VERSION 5.8 ;
BUSBITCHARS "[]" ;
DIVIDERCHAR "/" ;
UNITS
    DATABASE MICRONS 1000 ;
END UNITS

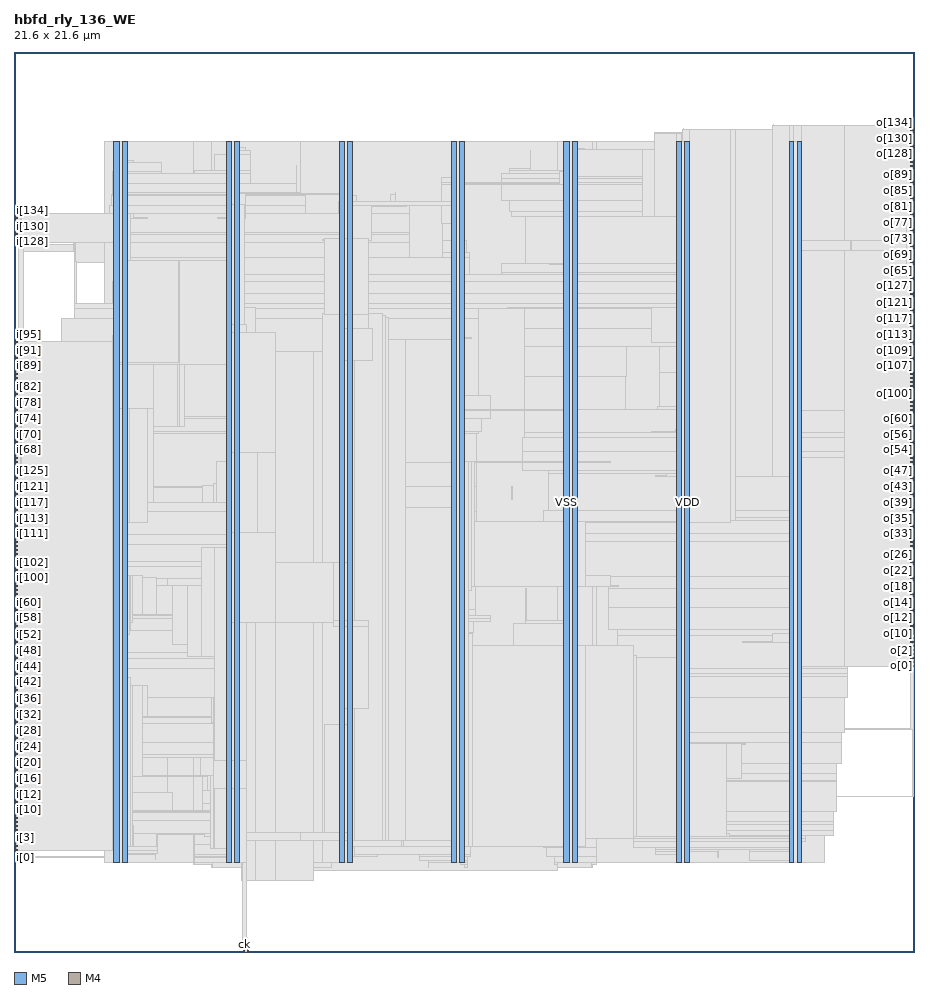
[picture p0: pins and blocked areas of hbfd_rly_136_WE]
MACRO hbfd_rly_136_WE
  FOREIGN hbfd_rly_136_WE 0 0 ;
  CLASS BLOCK ;
  SIZE 21.6 BY 21.6 ;
  PIN ck
    DIRECTION INPUT ;
    USE SIGNAL ;
    PORT
      LAYER M5 ;
        RECT  5.52 0 5.544 0.084 ;
    END
  END ck
  PIN i[0]
    DIRECTION INPUT ;
    USE SIGNAL ;
    PORT
      LAYER M4 ;
        RECT  0 2.448 0.084 2.472 ;
    END
  END i[0]
  PIN i[100]
    DIRECTION INPUT ;
    USE SIGNAL ;
    PORT
      LAYER M4 ;
        RECT  0 8.976 0.084 9 ;
    END
  END i[100]
  PIN i[101]
    DIRECTION INPUT ;
    USE SIGNAL ;
    PORT
      LAYER M4 ;
        RECT  0 9.072 0.084 9.096 ;
    END
  END i[101]
  PIN i[102]
    DIRECTION INPUT ;
    USE SIGNAL ;
    PORT
      LAYER M4 ;
        RECT  0 9.168 0.084 9.192 ;
    END
  END i[102]
  PIN i[103]
    DIRECTION INPUT ;
    USE SIGNAL ;
    PORT
      LAYER M4 ;
        RECT  0 9.264 0.084 9.288 ;
    END
  END i[103]
  PIN i[104]
    DIRECTION INPUT ;
    USE SIGNAL ;
    PORT
      LAYER M4 ;
        RECT  0 9.36 0.084 9.384 ;
    END
  END i[104]
  PIN i[105]
    DIRECTION INPUT ;
    USE SIGNAL ;
    PORT
      LAYER M4 ;
        RECT  0 9.456 0.084 9.48 ;
    END
  END i[105]
  PIN i[106]
    DIRECTION INPUT ;
    USE SIGNAL ;
    PORT
      LAYER M4 ;
        RECT  0 9.552 0.084 9.576 ;
    END
  END i[106]
  PIN i[107]
    DIRECTION INPUT ;
    USE SIGNAL ;
    PORT
      LAYER M4 ;
        RECT  0 9.648 0.084 9.672 ;
    END
  END i[107]
  PIN i[108]
    DIRECTION INPUT ;
    USE SIGNAL ;
    PORT
      LAYER M4 ;
        RECT  0 9.744 0.084 9.768 ;
    END
  END i[108]
  PIN i[109]
    DIRECTION INPUT ;
    USE SIGNAL ;
    PORT
      LAYER M4 ;
        RECT  0 9.84 0.084 9.864 ;
    END
  END i[109]
  PIN i[10]
    DIRECTION INPUT ;
    USE SIGNAL ;
    PORT
      LAYER M4 ;
        RECT  0 3.408 0.084 3.432 ;
    END
  END i[10]
  PIN i[110]
    DIRECTION INPUT ;
    USE SIGNAL ;
    PORT
      LAYER M4 ;
        RECT  0 9.936 0.084 9.96 ;
    END
  END i[110]
  PIN i[111]
    DIRECTION INPUT ;
    USE SIGNAL ;
    PORT
      LAYER M4 ;
        RECT  0 10.032 0.084 10.056 ;
    END
  END i[111]
  PIN i[112]
    DIRECTION INPUT ;
    USE SIGNAL ;
    PORT
      LAYER M4 ;
        RECT  0 10.128 0.084 10.152 ;
    END
  END i[112]
  PIN i[113]
    DIRECTION INPUT ;
    USE SIGNAL ;
    PORT
      LAYER M4 ;
        RECT  0 10.224 0.084 10.248 ;
    END
  END i[113]
  PIN i[114]
    DIRECTION INPUT ;
    USE SIGNAL ;
    PORT
      LAYER M4 ;
        RECT  0 10.32 0.084 10.344 ;
    END
  END i[114]
  PIN i[115]
    DIRECTION INPUT ;
    USE SIGNAL ;
    PORT
      LAYER M4 ;
        RECT  0 10.416 0.084 10.44 ;
    END
  END i[115]
  PIN i[116]
    DIRECTION INPUT ;
    USE SIGNAL ;
    PORT
      LAYER M4 ;
        RECT  0 10.512 0.084 10.536 ;
    END
  END i[116]
  PIN i[117]
    DIRECTION INPUT ;
    USE SIGNAL ;
    PORT
      LAYER M4 ;
        RECT  0 10.608 0.084 10.632 ;
    END
  END i[117]
  PIN i[118]
    DIRECTION INPUT ;
    USE SIGNAL ;
    PORT
      LAYER M4 ;
        RECT  0 10.704 0.084 10.728 ;
    END
  END i[118]
  PIN i[119]
    DIRECTION INPUT ;
    USE SIGNAL ;
    PORT
      LAYER M4 ;
        RECT  0 10.8 0.084 10.824 ;
    END
  END i[119]
  PIN i[11]
    DIRECTION INPUT ;
    USE SIGNAL ;
    PORT
      LAYER M4 ;
        RECT  0 3.504 0.084 3.528 ;
    END
  END i[11]
  PIN i[120]
    DIRECTION INPUT ;
    USE SIGNAL ;
    PORT
      LAYER M4 ;
        RECT  0 10.896 0.084 10.92 ;
    END
  END i[120]
  PIN i[121]
    DIRECTION INPUT ;
    USE SIGNAL ;
    PORT
      LAYER M4 ;
        RECT  0 10.992 0.084 11.016 ;
    END
  END i[121]
  PIN i[122]
    DIRECTION INPUT ;
    USE SIGNAL ;
    PORT
      LAYER M4 ;
        RECT  0 11.088 0.084 11.112 ;
    END
  END i[122]
  PIN i[123]
    DIRECTION INPUT ;
    USE SIGNAL ;
    PORT
      LAYER M4 ;
        RECT  0 11.184 0.084 11.208 ;
    END
  END i[123]
  PIN i[124]
    DIRECTION INPUT ;
    USE SIGNAL ;
    PORT
      LAYER M4 ;
        RECT  0 11.28 0.084 11.304 ;
    END
  END i[124]
  PIN i[125]
    DIRECTION INPUT ;
    USE SIGNAL ;
    PORT
      LAYER M4 ;
        RECT  0 11.376 0.084 11.4 ;
    END
  END i[125]
  PIN i[126]
    DIRECTION INPUT ;
    USE SIGNAL ;
    PORT
      LAYER M4 ;
        RECT  0 11.472 0.084 11.496 ;
    END
  END i[126]
  PIN i[127]
    DIRECTION INPUT ;
    USE SIGNAL ;
    PORT
      LAYER M4 ;
        RECT  0 11.568 0.084 11.592 ;
    END
  END i[127]
  PIN i[128]
    DIRECTION INPUT ;
    USE SIGNAL ;
    PORT
      LAYER M4 ;
        RECT  0 17.04 0.084 17.064 ;
    END
  END i[128]
  PIN i[129]
    DIRECTION INPUT ;
    USE SIGNAL ;
    PORT
      LAYER M4 ;
        RECT  0 17.136 0.084 17.16 ;
    END
  END i[129]
  PIN i[12]
    DIRECTION INPUT ;
    USE SIGNAL ;
    PORT
      LAYER M4 ;
        RECT  0 3.6 0.084 3.624 ;
    END
  END i[12]
  PIN i[130]
    DIRECTION INPUT ;
    USE SIGNAL ;
    PORT
      LAYER M4 ;
        RECT  0 17.232 0.084 17.256 ;
    END
  END i[130]
  PIN i[131]
    DIRECTION INPUT ;
    USE SIGNAL ;
    PORT
      LAYER M4 ;
        RECT  0 17.328 0.084 17.352 ;
    END
  END i[131]
  PIN i[132]
    DIRECTION INPUT ;
    USE SIGNAL ;
    PORT
      LAYER M4 ;
        RECT  0 17.424 0.084 17.448 ;
    END
  END i[132]
  PIN i[133]
    DIRECTION INPUT ;
    USE SIGNAL ;
    PORT
      LAYER M4 ;
        RECT  0 17.52 0.084 17.544 ;
    END
  END i[133]
  PIN i[134]
    DIRECTION INPUT ;
    USE SIGNAL ;
    PORT
      LAYER M4 ;
        RECT  0 17.616 0.084 17.64 ;
    END
  END i[134]
  PIN i[135]
    DIRECTION INPUT ;
    USE SIGNAL ;
    PORT
      LAYER M4 ;
        RECT  0 17.712 0.084 17.736 ;
    END
  END i[135]
  PIN i[13]
    DIRECTION INPUT ;
    USE SIGNAL ;
    PORT
      LAYER M4 ;
        RECT  0 3.696 0.084 3.72 ;
    END
  END i[13]
  PIN i[14]
    DIRECTION INPUT ;
    USE SIGNAL ;
    PORT
      LAYER M4 ;
        RECT  0 3.792 0.084 3.816 ;
    END
  END i[14]
  PIN i[15]
    DIRECTION INPUT ;
    USE SIGNAL ;
    PORT
      LAYER M4 ;
        RECT  0 3.888 0.084 3.912 ;
    END
  END i[15]
  PIN i[16]
    DIRECTION INPUT ;
    USE SIGNAL ;
    PORT
      LAYER M4 ;
        RECT  0 3.984 0.084 4.008 ;
    END
  END i[16]
  PIN i[17]
    DIRECTION INPUT ;
    USE SIGNAL ;
    PORT
      LAYER M4 ;
        RECT  0 4.08 0.084 4.104 ;
    END
  END i[17]
  PIN i[18]
    DIRECTION INPUT ;
    USE SIGNAL ;
    PORT
      LAYER M4 ;
        RECT  0 4.176 0.084 4.2 ;
    END
  END i[18]
  PIN i[19]
    DIRECTION INPUT ;
    USE SIGNAL ;
    PORT
      LAYER M4 ;
        RECT  0 4.272 0.084 4.296 ;
    END
  END i[19]
  PIN i[1]
    DIRECTION INPUT ;
    USE SIGNAL ;
    PORT
      LAYER M4 ;
        RECT  0 2.544 0.084 2.568 ;
    END
  END i[1]
  PIN i[20]
    DIRECTION INPUT ;
    USE SIGNAL ;
    PORT
      LAYER M4 ;
        RECT  0 4.368 0.084 4.392 ;
    END
  END i[20]
  PIN i[21]
    DIRECTION INPUT ;
    USE SIGNAL ;
    PORT
      LAYER M4 ;
        RECT  0 4.464 0.084 4.488 ;
    END
  END i[21]
  PIN i[22]
    DIRECTION INPUT ;
    USE SIGNAL ;
    PORT
      LAYER M4 ;
        RECT  0 4.56 0.084 4.584 ;
    END
  END i[22]
  PIN i[23]
    DIRECTION INPUT ;
    USE SIGNAL ;
    PORT
      LAYER M4 ;
        RECT  0 4.656 0.084 4.68 ;
    END
  END i[23]
  PIN i[24]
    DIRECTION INPUT ;
    USE SIGNAL ;
    PORT
      LAYER M4 ;
        RECT  0 4.752 0.084 4.776 ;
    END
  END i[24]
  PIN i[25]
    DIRECTION INPUT ;
    USE SIGNAL ;
    PORT
      LAYER M4 ;
        RECT  0 4.848 0.084 4.872 ;
    END
  END i[25]
  PIN i[26]
    DIRECTION INPUT ;
    USE SIGNAL ;
    PORT
      LAYER M4 ;
        RECT  0 4.944 0.084 4.968 ;
    END
  END i[26]
  PIN i[27]
    DIRECTION INPUT ;
    USE SIGNAL ;
    PORT
      LAYER M4 ;
        RECT  0 5.04 0.084 5.064 ;
    END
  END i[27]
  PIN i[28]
    DIRECTION INPUT ;
    USE SIGNAL ;
    PORT
      LAYER M4 ;
        RECT  0 5.136 0.084 5.16 ;
    END
  END i[28]
  PIN i[29]
    DIRECTION INPUT ;
    USE SIGNAL ;
    PORT
      LAYER M4 ;
        RECT  0 5.232 0.084 5.256 ;
    END
  END i[29]
  PIN i[2]
    DIRECTION INPUT ;
    USE SIGNAL ;
    PORT
      LAYER M4 ;
        RECT  0 2.64 0.084 2.664 ;
    END
  END i[2]
  PIN i[30]
    DIRECTION INPUT ;
    USE SIGNAL ;
    PORT
      LAYER M4 ;
        RECT  0 5.328 0.084 5.352 ;
    END
  END i[30]
  PIN i[31]
    DIRECTION INPUT ;
    USE SIGNAL ;
    PORT
      LAYER M4 ;
        RECT  0 5.424 0.084 5.448 ;
    END
  END i[31]
  PIN i[32]
    DIRECTION INPUT ;
    USE SIGNAL ;
    PORT
      LAYER M4 ;
        RECT  0 5.52 0.084 5.544 ;
    END
  END i[32]
  PIN i[33]
    DIRECTION INPUT ;
    USE SIGNAL ;
    PORT
      LAYER M4 ;
        RECT  0 5.616 0.084 5.64 ;
    END
  END i[33]
  PIN i[34]
    DIRECTION INPUT ;
    USE SIGNAL ;
    PORT
      LAYER M4 ;
        RECT  0 5.712 0.084 5.736 ;
    END
  END i[34]
  PIN i[35]
    DIRECTION INPUT ;
    USE SIGNAL ;
    PORT
      LAYER M4 ;
        RECT  0 5.808 0.084 5.832 ;
    END
  END i[35]
  PIN i[36]
    DIRECTION INPUT ;
    USE SIGNAL ;
    PORT
      LAYER M4 ;
        RECT  0 5.904 0.084 5.928 ;
    END
  END i[36]
  PIN i[37]
    DIRECTION INPUT ;
    USE SIGNAL ;
    PORT
      LAYER M4 ;
        RECT  0 6 0.084 6.024 ;
    END
  END i[37]
  PIN i[38]
    DIRECTION INPUT ;
    USE SIGNAL ;
    PORT
      LAYER M4 ;
        RECT  0 6.096 0.084 6.12 ;
    END
  END i[38]
  PIN i[39]
    DIRECTION INPUT ;
    USE SIGNAL ;
    PORT
      LAYER M4 ;
        RECT  0 6.192 0.084 6.216 ;
    END
  END i[39]
  PIN i[3]
    DIRECTION INPUT ;
    USE SIGNAL ;
    PORT
      LAYER M4 ;
        RECT  0 2.736 0.084 2.76 ;
    END
  END i[3]
  PIN i[40]
    DIRECTION INPUT ;
    USE SIGNAL ;
    PORT
      LAYER M4 ;
        RECT  0 6.288 0.084 6.312 ;
    END
  END i[40]
  PIN i[41]
    DIRECTION INPUT ;
    USE SIGNAL ;
    PORT
      LAYER M4 ;
        RECT  0 6.384 0.084 6.408 ;
    END
  END i[41]
  PIN i[42]
    DIRECTION INPUT ;
    USE SIGNAL ;
    PORT
      LAYER M4 ;
        RECT  0 6.48 0.084 6.504 ;
    END
  END i[42]
  PIN i[43]
    DIRECTION INPUT ;
    USE SIGNAL ;
    PORT
      LAYER M4 ;
        RECT  0 6.576 0.084 6.6 ;
    END
  END i[43]
  PIN i[44]
    DIRECTION INPUT ;
    USE SIGNAL ;
    PORT
      LAYER M4 ;
        RECT  0 6.672 0.084 6.696 ;
    END
  END i[44]
  PIN i[45]
    DIRECTION INPUT ;
    USE SIGNAL ;
    PORT
      LAYER M4 ;
        RECT  0 6.768 0.084 6.792 ;
    END
  END i[45]
  PIN i[46]
    DIRECTION INPUT ;
    USE SIGNAL ;
    PORT
      LAYER M4 ;
        RECT  0 6.864 0.084 6.888 ;
    END
  END i[46]
  PIN i[47]
    DIRECTION INPUT ;
    USE SIGNAL ;
    PORT
      LAYER M4 ;
        RECT  0 6.96 0.084 6.984 ;
    END
  END i[47]
  PIN i[48]
    DIRECTION INPUT ;
    USE SIGNAL ;
    PORT
      LAYER M4 ;
        RECT  0 7.056 0.084 7.08 ;
    END
  END i[48]
  PIN i[49]
    DIRECTION INPUT ;
    USE SIGNAL ;
    PORT
      LAYER M4 ;
        RECT  0 7.152 0.084 7.176 ;
    END
  END i[49]
  PIN i[4]
    DIRECTION INPUT ;
    USE SIGNAL ;
    PORT
      LAYER M4 ;
        RECT  0 2.832 0.084 2.856 ;
    END
  END i[4]
  PIN i[50]
    DIRECTION INPUT ;
    USE SIGNAL ;
    PORT
      LAYER M4 ;
        RECT  0 7.248 0.084 7.272 ;
    END
  END i[50]
  PIN i[51]
    DIRECTION INPUT ;
    USE SIGNAL ;
    PORT
      LAYER M4 ;
        RECT  0 7.344 0.084 7.368 ;
    END
  END i[51]
  PIN i[52]
    DIRECTION INPUT ;
    USE SIGNAL ;
    PORT
      LAYER M4 ;
        RECT  0 7.44 0.084 7.464 ;
    END
  END i[52]
  PIN i[53]
    DIRECTION INPUT ;
    USE SIGNAL ;
    PORT
      LAYER M4 ;
        RECT  0 7.536 0.084 7.56 ;
    END
  END i[53]
  PIN i[54]
    DIRECTION INPUT ;
    USE SIGNAL ;
    PORT
      LAYER M4 ;
        RECT  0 7.632 0.084 7.656 ;
    END
  END i[54]
  PIN i[55]
    DIRECTION INPUT ;
    USE SIGNAL ;
    PORT
      LAYER M4 ;
        RECT  0 7.728 0.084 7.752 ;
    END
  END i[55]
  PIN i[56]
    DIRECTION INPUT ;
    USE SIGNAL ;
    PORT
      LAYER M4 ;
        RECT  0 7.824 0.084 7.848 ;
    END
  END i[56]
  PIN i[57]
    DIRECTION INPUT ;
    USE SIGNAL ;
    PORT
      LAYER M4 ;
        RECT  0 7.92 0.084 7.944 ;
    END
  END i[57]
  PIN i[58]
    DIRECTION INPUT ;
    USE SIGNAL ;
    PORT
      LAYER M4 ;
        RECT  0 8.016 0.084 8.04 ;
    END
  END i[58]
  PIN i[59]
    DIRECTION INPUT ;
    USE SIGNAL ;
    PORT
      LAYER M4 ;
        RECT  0 8.112 0.084 8.136 ;
    END
  END i[59]
  PIN i[5]
    DIRECTION INPUT ;
    USE SIGNAL ;
    PORT
      LAYER M4 ;
        RECT  0 2.928 0.084 2.952 ;
    END
  END i[5]
  PIN i[60]
    DIRECTION INPUT ;
    USE SIGNAL ;
    PORT
      LAYER M4 ;
        RECT  0 8.208 0.084 8.232 ;
    END
  END i[60]
  PIN i[61]
    DIRECTION INPUT ;
    USE SIGNAL ;
    PORT
      LAYER M4 ;
        RECT  0 8.304 0.084 8.328 ;
    END
  END i[61]
  PIN i[62]
    DIRECTION INPUT ;
    USE SIGNAL ;
    PORT
      LAYER M4 ;
        RECT  0 8.4 0.084 8.424 ;
    END
  END i[62]
  PIN i[63]
    DIRECTION INPUT ;
    USE SIGNAL ;
    PORT
      LAYER M4 ;
        RECT  0 8.496 0.084 8.52 ;
    END
  END i[63]
  PIN i[64]
    DIRECTION INPUT ;
    USE SIGNAL ;
    PORT
      LAYER M4 ;
        RECT  0 11.664 0.084 11.688 ;
    END
  END i[64]
  PIN i[65]
    DIRECTION INPUT ;
    USE SIGNAL ;
    PORT
      LAYER M4 ;
        RECT  0 11.76 0.084 11.784 ;
    END
  END i[65]
  PIN i[66]
    DIRECTION INPUT ;
    USE SIGNAL ;
    PORT
      LAYER M4 ;
        RECT  0 11.856 0.084 11.88 ;
    END
  END i[66]
  PIN i[67]
    DIRECTION INPUT ;
    USE SIGNAL ;
    PORT
      LAYER M4 ;
        RECT  0 11.952 0.084 11.976 ;
    END
  END i[67]
  PIN i[68]
    DIRECTION INPUT ;
    USE SIGNAL ;
    PORT
      LAYER M4 ;
        RECT  0 12.048 0.084 12.072 ;
    END
  END i[68]
  PIN i[69]
    DIRECTION INPUT ;
    USE SIGNAL ;
    PORT
      LAYER M4 ;
        RECT  0 12.144 0.084 12.168 ;
    END
  END i[69]
  PIN i[6]
    DIRECTION INPUT ;
    USE SIGNAL ;
    PORT
      LAYER M4 ;
        RECT  0 3.024 0.084 3.048 ;
    END
  END i[6]
  PIN i[70]
    DIRECTION INPUT ;
    USE SIGNAL ;
    PORT
      LAYER M4 ;
        RECT  0 12.24 0.084 12.264 ;
    END
  END i[70]
  PIN i[71]
    DIRECTION INPUT ;
    USE SIGNAL ;
    PORT
      LAYER M4 ;
        RECT  0 12.336 0.084 12.36 ;
    END
  END i[71]
  PIN i[72]
    DIRECTION INPUT ;
    USE SIGNAL ;
    PORT
      LAYER M4 ;
        RECT  0 12.432 0.084 12.456 ;
    END
  END i[72]
  PIN i[73]
    DIRECTION INPUT ;
    USE SIGNAL ;
    PORT
      LAYER M4 ;
        RECT  0 12.528 0.084 12.552 ;
    END
  END i[73]
  PIN i[74]
    DIRECTION INPUT ;
    USE SIGNAL ;
    PORT
      LAYER M4 ;
        RECT  0 12.624 0.084 12.648 ;
    END
  END i[74]
  PIN i[75]
    DIRECTION INPUT ;
    USE SIGNAL ;
    PORT
      LAYER M4 ;
        RECT  0 12.72 0.084 12.744 ;
    END
  END i[75]
  PIN i[76]
    DIRECTION INPUT ;
    USE SIGNAL ;
    PORT
      LAYER M4 ;
        RECT  0 12.816 0.084 12.84 ;
    END
  END i[76]
  PIN i[77]
    DIRECTION INPUT ;
    USE SIGNAL ;
    PORT
      LAYER M4 ;
        RECT  0 12.912 0.084 12.936 ;
    END
  END i[77]
  PIN i[78]
    DIRECTION INPUT ;
    USE SIGNAL ;
    PORT
      LAYER M4 ;
        RECT  0 13.008 0.084 13.032 ;
    END
  END i[78]
  PIN i[79]
    DIRECTION INPUT ;
    USE SIGNAL ;
    PORT
      LAYER M4 ;
        RECT  0 13.104 0.084 13.128 ;
    END
  END i[79]
  PIN i[7]
    DIRECTION INPUT ;
    USE SIGNAL ;
    PORT
      LAYER M4 ;
        RECT  0 3.12 0.084 3.144 ;
    END
  END i[7]
  PIN i[80]
    DIRECTION INPUT ;
    USE SIGNAL ;
    PORT
      LAYER M4 ;
        RECT  0 13.2 0.084 13.224 ;
    END
  END i[80]
  PIN i[81]
    DIRECTION INPUT ;
    USE SIGNAL ;
    PORT
      LAYER M4 ;
        RECT  0 13.296 0.084 13.32 ;
    END
  END i[81]
  PIN i[82]
    DIRECTION INPUT ;
    USE SIGNAL ;
    PORT
      LAYER M4 ;
        RECT  0 13.392 0.084 13.416 ;
    END
  END i[82]
  PIN i[83]
    DIRECTION INPUT ;
    USE SIGNAL ;
    PORT
      LAYER M4 ;
        RECT  0 13.488 0.084 13.512 ;
    END
  END i[83]
  PIN i[84]
    DIRECTION INPUT ;
    USE SIGNAL ;
    PORT
      LAYER M4 ;
        RECT  0 13.584 0.084 13.608 ;
    END
  END i[84]
  PIN i[85]
    DIRECTION INPUT ;
    USE SIGNAL ;
    PORT
      LAYER M4 ;
        RECT  0 13.68 0.084 13.704 ;
    END
  END i[85]
  PIN i[86]
    DIRECTION INPUT ;
    USE SIGNAL ;
    PORT
      LAYER M4 ;
        RECT  0 13.776 0.084 13.8 ;
    END
  END i[86]
  PIN i[87]
    DIRECTION INPUT ;
    USE SIGNAL ;
    PORT
      LAYER M4 ;
        RECT  0 13.872 0.084 13.896 ;
    END
  END i[87]
  PIN i[88]
    DIRECTION INPUT ;
    USE SIGNAL ;
    PORT
      LAYER M4 ;
        RECT  0 13.968 0.084 13.992 ;
    END
  END i[88]
  PIN i[89]
    DIRECTION INPUT ;
    USE SIGNAL ;
    PORT
      LAYER M4 ;
        RECT  0 14.064 0.084 14.088 ;
    END
  END i[89]
  PIN i[8]
    DIRECTION INPUT ;
    USE SIGNAL ;
    PORT
      LAYER M4 ;
        RECT  0 3.216 0.084 3.24 ;
    END
  END i[8]
  PIN i[90]
    DIRECTION INPUT ;
    USE SIGNAL ;
    PORT
      LAYER M4 ;
        RECT  0 14.16 0.084 14.184 ;
    END
  END i[90]
  PIN i[91]
    DIRECTION INPUT ;
    USE SIGNAL ;
    PORT
      LAYER M4 ;
        RECT  0 14.256 0.084 14.28 ;
    END
  END i[91]
  PIN i[92]
    DIRECTION INPUT ;
    USE SIGNAL ;
    PORT
      LAYER M4 ;
        RECT  0 14.352 0.084 14.376 ;
    END
  END i[92]
  PIN i[93]
    DIRECTION INPUT ;
    USE SIGNAL ;
    PORT
      LAYER M4 ;
        RECT  0 14.448 0.084 14.472 ;
    END
  END i[93]
  PIN i[94]
    DIRECTION INPUT ;
    USE SIGNAL ;
    PORT
      LAYER M4 ;
        RECT  0 14.544 0.084 14.568 ;
    END
  END i[94]
  PIN i[95]
    DIRECTION INPUT ;
    USE SIGNAL ;
    PORT
      LAYER M4 ;
        RECT  0 14.64 0.084 14.664 ;
    END
  END i[95]
  PIN i[96]
    DIRECTION INPUT ;
    USE SIGNAL ;
    PORT
      LAYER M4 ;
        RECT  0 8.592 0.084 8.616 ;
    END
  END i[96]
  PIN i[97]
    DIRECTION INPUT ;
    USE SIGNAL ;
    PORT
      LAYER M4 ;
        RECT  0 8.688 0.084 8.712 ;
    END
  END i[97]
  PIN i[98]
    DIRECTION INPUT ;
    USE SIGNAL ;
    PORT
      LAYER M4 ;
        RECT  0 8.784 0.084 8.808 ;
    END
  END i[98]
  PIN i[99]
    DIRECTION INPUT ;
    USE SIGNAL ;
    PORT
      LAYER M4 ;
        RECT  0 8.88 0.084 8.904 ;
    END
  END i[99]
  PIN i[9]
    DIRECTION INPUT ;
    USE SIGNAL ;
    PORT
      LAYER M4 ;
        RECT  0 3.312 0.084 3.336 ;
    END
  END i[9]
  PIN o[0]
    DIRECTION OUTPUT ;
    USE SIGNAL ;
    PORT
      LAYER M4 ;
        RECT  21.516 6.864 21.6 6.888 ;
    END
  END o[0]
  PIN o[100]
    DIRECTION OUTPUT ;
    USE SIGNAL ;
    PORT
      LAYER M4 ;
        RECT  21.516 13.392 21.6 13.416 ;
    END
  END o[100]
  PIN o[101]
    DIRECTION OUTPUT ;
    USE SIGNAL ;
    PORT
      LAYER M4 ;
        RECT  21.516 13.488 21.6 13.512 ;
    END
  END o[101]
  PIN o[102]
    DIRECTION OUTPUT ;
    USE SIGNAL ;
    PORT
      LAYER M4 ;
        RECT  21.516 13.584 21.6 13.608 ;
    END
  END o[102]
  PIN o[103]
    DIRECTION OUTPUT ;
    USE SIGNAL ;
    PORT
      LAYER M4 ;
        RECT  21.516 13.68 21.6 13.704 ;
    END
  END o[103]
  PIN o[104]
    DIRECTION OUTPUT ;
    USE SIGNAL ;
    PORT
      LAYER M4 ;
        RECT  21.516 13.776 21.6 13.8 ;
    END
  END o[104]
  PIN o[105]
    DIRECTION OUTPUT ;
    USE SIGNAL ;
    PORT
      LAYER M4 ;
        RECT  21.516 13.872 21.6 13.896 ;
    END
  END o[105]
  PIN o[106]
    DIRECTION OUTPUT ;
    USE SIGNAL ;
    PORT
      LAYER M4 ;
        RECT  21.516 13.968 21.6 13.992 ;
    END
  END o[106]
  PIN o[107]
    DIRECTION OUTPUT ;
    USE SIGNAL ;
    PORT
      LAYER M4 ;
        RECT  21.516 14.064 21.6 14.088 ;
    END
  END o[107]
  PIN o[108]
    DIRECTION OUTPUT ;
    USE SIGNAL ;
    PORT
      LAYER M4 ;
        RECT  21.516 14.16 21.6 14.184 ;
    END
  END o[108]
  PIN o[109]
    DIRECTION OUTPUT ;
    USE SIGNAL ;
    PORT
      LAYER M4 ;
        RECT  21.516 14.256 21.6 14.28 ;
    END
  END o[109]
  PIN o[10]
    DIRECTION OUTPUT ;
    USE SIGNAL ;
    PORT
      LAYER M4 ;
        RECT  21.516 7.824 21.6 7.848 ;
    END
  END o[10]
  PIN o[110]
    DIRECTION OUTPUT ;
    USE SIGNAL ;
    PORT
      LAYER M4 ;
        RECT  21.516 14.352 21.6 14.376 ;
    END
  END o[110]
  PIN o[111]
    DIRECTION OUTPUT ;
    USE SIGNAL ;
    PORT
      LAYER M4 ;
        RECT  21.516 14.448 21.6 14.472 ;
    END
  END o[111]
  PIN o[112]
    DIRECTION OUTPUT ;
    USE SIGNAL ;
    PORT
      LAYER M4 ;
        RECT  21.516 14.544 21.6 14.568 ;
    END
  END o[112]
  PIN o[113]
    DIRECTION OUTPUT ;
    USE SIGNAL ;
    PORT
      LAYER M4 ;
        RECT  21.516 14.64 21.6 14.664 ;
    END
  END o[113]
  PIN o[114]
    DIRECTION OUTPUT ;
    USE SIGNAL ;
    PORT
      LAYER M4 ;
        RECT  21.516 14.736 21.6 14.76 ;
    END
  END o[114]
  PIN o[115]
    DIRECTION OUTPUT ;
    USE SIGNAL ;
    PORT
      LAYER M4 ;
        RECT  21.516 14.832 21.6 14.856 ;
    END
  END o[115]
  PIN o[116]
    DIRECTION OUTPUT ;
    USE SIGNAL ;
    PORT
      LAYER M4 ;
        RECT  21.516 14.928 21.6 14.952 ;
    END
  END o[116]
  PIN o[117]
    DIRECTION OUTPUT ;
    USE SIGNAL ;
    PORT
      LAYER M4 ;
        RECT  21.516 15.024 21.6 15.048 ;
    END
  END o[117]
  PIN o[118]
    DIRECTION OUTPUT ;
    USE SIGNAL ;
    PORT
      LAYER M4 ;
        RECT  21.516 15.12 21.6 15.144 ;
    END
  END o[118]
  PIN o[119]
    DIRECTION OUTPUT ;
    USE SIGNAL ;
    PORT
      LAYER M4 ;
        RECT  21.516 15.216 21.6 15.24 ;
    END
  END o[119]
  PIN o[11]
    DIRECTION OUTPUT ;
    USE SIGNAL ;
    PORT
      LAYER M4 ;
        RECT  21.516 7.92 21.6 7.944 ;
    END
  END o[11]
  PIN o[120]
    DIRECTION OUTPUT ;
    USE SIGNAL ;
    PORT
      LAYER M4 ;
        RECT  21.516 15.312 21.6 15.336 ;
    END
  END o[120]
  PIN o[121]
    DIRECTION OUTPUT ;
    USE SIGNAL ;
    PORT
      LAYER M4 ;
        RECT  21.516 15.408 21.6 15.432 ;
    END
  END o[121]
  PIN o[122]
    DIRECTION OUTPUT ;
    USE SIGNAL ;
    PORT
      LAYER M4 ;
        RECT  21.516 15.504 21.6 15.528 ;
    END
  END o[122]
  PIN o[123]
    DIRECTION OUTPUT ;
    USE SIGNAL ;
    PORT
      LAYER M4 ;
        RECT  21.516 15.6 21.6 15.624 ;
    END
  END o[123]
  PIN o[124]
    DIRECTION OUTPUT ;
    USE SIGNAL ;
    PORT
      LAYER M4 ;
        RECT  21.516 15.696 21.6 15.72 ;
    END
  END o[124]
  PIN o[125]
    DIRECTION OUTPUT ;
    USE SIGNAL ;
    PORT
      LAYER M4 ;
        RECT  21.516 15.792 21.6 15.816 ;
    END
  END o[125]
  PIN o[126]
    DIRECTION OUTPUT ;
    USE SIGNAL ;
    PORT
      LAYER M4 ;
        RECT  21.516 15.888 21.6 15.912 ;
    END
  END o[126]
  PIN o[127]
    DIRECTION OUTPUT ;
    USE SIGNAL ;
    PORT
      LAYER M4 ;
        RECT  21.516 15.984 21.6 16.008 ;
    END
  END o[127]
  PIN o[128]
    DIRECTION OUTPUT ;
    USE SIGNAL ;
    PORT
      LAYER M4 ;
        RECT  21.516 19.152 21.6 19.176 ;
    END
  END o[128]
  PIN o[129]
    DIRECTION OUTPUT ;
    USE SIGNAL ;
    PORT
      LAYER M4 ;
        RECT  21.516 19.248 21.6 19.272 ;
    END
  END o[129]
  PIN o[12]
    DIRECTION OUTPUT ;
    USE SIGNAL ;
    PORT
      LAYER M4 ;
        RECT  21.516 8.016 21.6 8.04 ;
    END
  END o[12]
  PIN o[130]
    DIRECTION OUTPUT ;
    USE SIGNAL ;
    PORT
      LAYER M4 ;
        RECT  21.516 19.344 21.6 19.368 ;
    END
  END o[130]
  PIN o[131]
    DIRECTION OUTPUT ;
    USE SIGNAL ;
    PORT
      LAYER M4 ;
        RECT  21.516 19.44 21.6 19.464 ;
    END
  END o[131]
  PIN o[132]
    DIRECTION OUTPUT ;
    USE SIGNAL ;
    PORT
      LAYER M4 ;
        RECT  21.516 19.536 21.6 19.56 ;
    END
  END o[132]
  PIN o[133]
    DIRECTION OUTPUT ;
    USE SIGNAL ;
    PORT
      LAYER M4 ;
        RECT  21.516 19.632 21.6 19.656 ;
    END
  END o[133]
  PIN o[134]
    DIRECTION OUTPUT ;
    USE SIGNAL ;
    PORT
      LAYER M4 ;
        RECT  21.516 19.728 21.6 19.752 ;
    END
  END o[134]
  PIN o[135]
    DIRECTION OUTPUT ;
    USE SIGNAL ;
    PORT
      LAYER M4 ;
        RECT  21.516 19.824 21.6 19.848 ;
    END
  END o[135]
  PIN o[13]
    DIRECTION OUTPUT ;
    USE SIGNAL ;
    PORT
      LAYER M4 ;
        RECT  21.516 8.112 21.6 8.136 ;
    END
  END o[13]
  PIN o[14]
    DIRECTION OUTPUT ;
    USE SIGNAL ;
    PORT
      LAYER M4 ;
        RECT  21.516 8.208 21.6 8.232 ;
    END
  END o[14]
  PIN o[15]
    DIRECTION OUTPUT ;
    USE SIGNAL ;
    PORT
      LAYER M4 ;
        RECT  21.516 8.304 21.6 8.328 ;
    END
  END o[15]
  PIN o[16]
    DIRECTION OUTPUT ;
    USE SIGNAL ;
    PORT
      LAYER M4 ;
        RECT  21.516 8.4 21.6 8.424 ;
    END
  END o[16]
  PIN o[17]
    DIRECTION OUTPUT ;
    USE SIGNAL ;
    PORT
      LAYER M4 ;
        RECT  21.516 8.496 21.6 8.52 ;
    END
  END o[17]
  PIN o[18]
    DIRECTION OUTPUT ;
    USE SIGNAL ;
    PORT
      LAYER M4 ;
        RECT  21.516 8.592 21.6 8.616 ;
    END
  END o[18]
  PIN o[19]
    DIRECTION OUTPUT ;
    USE SIGNAL ;
    PORT
      LAYER M4 ;
        RECT  21.516 8.688 21.6 8.712 ;
    END
  END o[19]
  PIN o[1]
    DIRECTION OUTPUT ;
    USE SIGNAL ;
    PORT
      LAYER M4 ;
        RECT  21.516 6.96 21.6 6.984 ;
    END
  END o[1]
  PIN o[20]
    DIRECTION OUTPUT ;
    USE SIGNAL ;
    PORT
      LAYER M4 ;
        RECT  21.516 8.784 21.6 8.808 ;
    END
  END o[20]
  PIN o[21]
    DIRECTION OUTPUT ;
    USE SIGNAL ;
    PORT
      LAYER M4 ;
        RECT  21.516 8.88 21.6 8.904 ;
    END
  END o[21]
  PIN o[22]
    DIRECTION OUTPUT ;
    USE SIGNAL ;
    PORT
      LAYER M4 ;
        RECT  21.516 8.976 21.6 9 ;
    END
  END o[22]
  PIN o[23]
    DIRECTION OUTPUT ;
    USE SIGNAL ;
    PORT
      LAYER M4 ;
        RECT  21.516 9.072 21.6 9.096 ;
    END
  END o[23]
  PIN o[24]
    DIRECTION OUTPUT ;
    USE SIGNAL ;
    PORT
      LAYER M4 ;
        RECT  21.516 9.168 21.6 9.192 ;
    END
  END o[24]
  PIN o[25]
    DIRECTION OUTPUT ;
    USE SIGNAL ;
    PORT
      LAYER M4 ;
        RECT  21.516 9.264 21.6 9.288 ;
    END
  END o[25]
  PIN o[26]
    DIRECTION OUTPUT ;
    USE SIGNAL ;
    PORT
      LAYER M4 ;
        RECT  21.516 9.36 21.6 9.384 ;
    END
  END o[26]
  PIN o[27]
    DIRECTION OUTPUT ;
    USE SIGNAL ;
    PORT
      LAYER M4 ;
        RECT  21.516 9.456 21.6 9.48 ;
    END
  END o[27]
  PIN o[28]
    DIRECTION OUTPUT ;
    USE SIGNAL ;
    PORT
      LAYER M4 ;
        RECT  21.516 9.552 21.6 9.576 ;
    END
  END o[28]
  PIN o[29]
    DIRECTION OUTPUT ;
    USE SIGNAL ;
    PORT
      LAYER M4 ;
        RECT  21.516 9.648 21.6 9.672 ;
    END
  END o[29]
  PIN o[2]
    DIRECTION OUTPUT ;
    USE SIGNAL ;
    PORT
      LAYER M4 ;
        RECT  21.516 7.056 21.6 7.08 ;
    END
  END o[2]
  PIN o[30]
    DIRECTION OUTPUT ;
    USE SIGNAL ;
    PORT
      LAYER M4 ;
        RECT  21.516 9.744 21.6 9.768 ;
    END
  END o[30]
  PIN o[31]
    DIRECTION OUTPUT ;
    USE SIGNAL ;
    PORT
      LAYER M4 ;
        RECT  21.516 9.84 21.6 9.864 ;
    END
  END o[31]
  PIN o[32]
    DIRECTION OUTPUT ;
    USE SIGNAL ;
    PORT
      LAYER M4 ;
        RECT  21.516 9.936 21.6 9.96 ;
    END
  END o[32]
  PIN o[33]
    DIRECTION OUTPUT ;
    USE SIGNAL ;
    PORT
      LAYER M4 ;
        RECT  21.516 10.032 21.6 10.056 ;
    END
  END o[33]
  PIN o[34]
    DIRECTION OUTPUT ;
    USE SIGNAL ;
    PORT
      LAYER M4 ;
        RECT  21.516 10.128 21.6 10.152 ;
    END
  END o[34]
  PIN o[35]
    DIRECTION OUTPUT ;
    USE SIGNAL ;
    PORT
      LAYER M4 ;
        RECT  21.516 10.224 21.6 10.248 ;
    END
  END o[35]
  PIN o[36]
    DIRECTION OUTPUT ;
    USE SIGNAL ;
    PORT
      LAYER M4 ;
        RECT  21.516 10.32 21.6 10.344 ;
    END
  END o[36]
  PIN o[37]
    DIRECTION OUTPUT ;
    USE SIGNAL ;
    PORT
      LAYER M4 ;
        RECT  21.516 10.416 21.6 10.44 ;
    END
  END o[37]
  PIN o[38]
    DIRECTION OUTPUT ;
    USE SIGNAL ;
    PORT
      LAYER M4 ;
        RECT  21.516 10.512 21.6 10.536 ;
    END
  END o[38]
  PIN o[39]
    DIRECTION OUTPUT ;
    USE SIGNAL ;
    PORT
      LAYER M4 ;
        RECT  21.516 10.608 21.6 10.632 ;
    END
  END o[39]
  PIN o[3]
    DIRECTION OUTPUT ;
    USE SIGNAL ;
    PORT
      LAYER M4 ;
        RECT  21.516 7.152 21.6 7.176 ;
    END
  END o[3]
  PIN o[40]
    DIRECTION OUTPUT ;
    USE SIGNAL ;
    PORT
      LAYER M4 ;
        RECT  21.516 10.704 21.6 10.728 ;
    END
  END o[40]
  PIN o[41]
    DIRECTION OUTPUT ;
    USE SIGNAL ;
    PORT
      LAYER M4 ;
        RECT  21.516 10.8 21.6 10.824 ;
    END
  END o[41]
  PIN o[42]
    DIRECTION OUTPUT ;
    USE SIGNAL ;
    PORT
      LAYER M4 ;
        RECT  21.516 10.896 21.6 10.92 ;
    END
  END o[42]
  PIN o[43]
    DIRECTION OUTPUT ;
    USE SIGNAL ;
    PORT
      LAYER M4 ;
        RECT  21.516 10.992 21.6 11.016 ;
    END
  END o[43]
  PIN o[44]
    DIRECTION OUTPUT ;
    USE SIGNAL ;
    PORT
      LAYER M4 ;
        RECT  21.516 11.088 21.6 11.112 ;
    END
  END o[44]
  PIN o[45]
    DIRECTION OUTPUT ;
    USE SIGNAL ;
    PORT
      LAYER M4 ;
        RECT  21.516 11.184 21.6 11.208 ;
    END
  END o[45]
  PIN o[46]
    DIRECTION OUTPUT ;
    USE SIGNAL ;
    PORT
      LAYER M4 ;
        RECT  21.516 11.28 21.6 11.304 ;
    END
  END o[46]
  PIN o[47]
    DIRECTION OUTPUT ;
    USE SIGNAL ;
    PORT
      LAYER M4 ;
        RECT  21.516 11.376 21.6 11.4 ;
    END
  END o[47]
  PIN o[48]
    DIRECTION OUTPUT ;
    USE SIGNAL ;
    PORT
      LAYER M4 ;
        RECT  21.516 11.472 21.6 11.496 ;
    END
  END o[48]
  PIN o[49]
    DIRECTION OUTPUT ;
    USE SIGNAL ;
    PORT
      LAYER M4 ;
        RECT  21.516 11.568 21.6 11.592 ;
    END
  END o[49]
  PIN o[4]
    DIRECTION OUTPUT ;
    USE SIGNAL ;
    PORT
      LAYER M4 ;
        RECT  21.516 7.248 21.6 7.272 ;
    END
  END o[4]
  PIN o[50]
    DIRECTION OUTPUT ;
    USE SIGNAL ;
    PORT
      LAYER M4 ;
        RECT  21.516 11.664 21.6 11.688 ;
    END
  END o[50]
  PIN o[51]
    DIRECTION OUTPUT ;
    USE SIGNAL ;
    PORT
      LAYER M4 ;
        RECT  21.516 11.76 21.6 11.784 ;
    END
  END o[51]
  PIN o[52]
    DIRECTION OUTPUT ;
    USE SIGNAL ;
    PORT
      LAYER M4 ;
        RECT  21.516 11.856 21.6 11.88 ;
    END
  END o[52]
  PIN o[53]
    DIRECTION OUTPUT ;
    USE SIGNAL ;
    PORT
      LAYER M4 ;
        RECT  21.516 11.952 21.6 11.976 ;
    END
  END o[53]
  PIN o[54]
    DIRECTION OUTPUT ;
    USE SIGNAL ;
    PORT
      LAYER M4 ;
        RECT  21.516 12.048 21.6 12.072 ;
    END
  END o[54]
  PIN o[55]
    DIRECTION OUTPUT ;
    USE SIGNAL ;
    PORT
      LAYER M4 ;
        RECT  21.516 12.144 21.6 12.168 ;
    END
  END o[55]
  PIN o[56]
    DIRECTION OUTPUT ;
    USE SIGNAL ;
    PORT
      LAYER M4 ;
        RECT  21.516 12.24 21.6 12.264 ;
    END
  END o[56]
  PIN o[57]
    DIRECTION OUTPUT ;
    USE SIGNAL ;
    PORT
      LAYER M4 ;
        RECT  21.516 12.336 21.6 12.36 ;
    END
  END o[57]
  PIN o[58]
    DIRECTION OUTPUT ;
    USE SIGNAL ;
    PORT
      LAYER M4 ;
        RECT  21.516 12.432 21.6 12.456 ;
    END
  END o[58]
  PIN o[59]
    DIRECTION OUTPUT ;
    USE SIGNAL ;
    PORT
      LAYER M4 ;
        RECT  21.516 12.528 21.6 12.552 ;
    END
  END o[59]
  PIN o[5]
    DIRECTION OUTPUT ;
    USE SIGNAL ;
    PORT
      LAYER M4 ;
        RECT  21.516 7.344 21.6 7.368 ;
    END
  END o[5]
  PIN o[60]
    DIRECTION OUTPUT ;
    USE SIGNAL ;
    PORT
      LAYER M4 ;
        RECT  21.516 12.624 21.6 12.648 ;
    END
  END o[60]
  PIN o[61]
    DIRECTION OUTPUT ;
    USE SIGNAL ;
    PORT
      LAYER M4 ;
        RECT  21.516 12.72 21.6 12.744 ;
    END
  END o[61]
  PIN o[62]
    DIRECTION OUTPUT ;
    USE SIGNAL ;
    PORT
      LAYER M4 ;
        RECT  21.516 12.816 21.6 12.84 ;
    END
  END o[62]
  PIN o[63]
    DIRECTION OUTPUT ;
    USE SIGNAL ;
    PORT
      LAYER M4 ;
        RECT  21.516 12.912 21.6 12.936 ;
    END
  END o[63]
  PIN o[64]
    DIRECTION OUTPUT ;
    USE SIGNAL ;
    PORT
      LAYER M4 ;
        RECT  21.516 16.08 21.6 16.104 ;
    END
  END o[64]
  PIN o[65]
    DIRECTION OUTPUT ;
    USE SIGNAL ;
    PORT
      LAYER M4 ;
        RECT  21.516 16.176 21.6 16.2 ;
    END
  END o[65]
  PIN o[66]
    DIRECTION OUTPUT ;
    USE SIGNAL ;
    PORT
      LAYER M4 ;
        RECT  21.516 16.272 21.6 16.296 ;
    END
  END o[66]
  PIN o[67]
    DIRECTION OUTPUT ;
    USE SIGNAL ;
    PORT
      LAYER M4 ;
        RECT  21.516 16.368 21.6 16.392 ;
    END
  END o[67]
  PIN o[68]
    DIRECTION OUTPUT ;
    USE SIGNAL ;
    PORT
      LAYER M4 ;
        RECT  21.516 16.464 21.6 16.488 ;
    END
  END o[68]
  PIN o[69]
    DIRECTION OUTPUT ;
    USE SIGNAL ;
    PORT
      LAYER M4 ;
        RECT  21.516 16.56 21.6 16.584 ;
    END
  END o[69]
  PIN o[6]
    DIRECTION OUTPUT ;
    USE SIGNAL ;
    PORT
      LAYER M4 ;
        RECT  21.516 7.44 21.6 7.464 ;
    END
  END o[6]
  PIN o[70]
    DIRECTION OUTPUT ;
    USE SIGNAL ;
    PORT
      LAYER M4 ;
        RECT  21.516 16.656 21.6 16.68 ;
    END
  END o[70]
  PIN o[71]
    DIRECTION OUTPUT ;
    USE SIGNAL ;
    PORT
      LAYER M4 ;
        RECT  21.516 16.752 21.6 16.776 ;
    END
  END o[71]
  PIN o[72]
    DIRECTION OUTPUT ;
    USE SIGNAL ;
    PORT
      LAYER M4 ;
        RECT  21.516 16.848 21.6 16.872 ;
    END
  END o[72]
  PIN o[73]
    DIRECTION OUTPUT ;
    USE SIGNAL ;
    PORT
      LAYER M4 ;
        RECT  21.516 16.944 21.6 16.968 ;
    END
  END o[73]
  PIN o[74]
    DIRECTION OUTPUT ;
    USE SIGNAL ;
    PORT
      LAYER M4 ;
        RECT  21.516 17.04 21.6 17.064 ;
    END
  END o[74]
  PIN o[75]
    DIRECTION OUTPUT ;
    USE SIGNAL ;
    PORT
      LAYER M4 ;
        RECT  21.516 17.136 21.6 17.16 ;
    END
  END o[75]
  PIN o[76]
    DIRECTION OUTPUT ;
    USE SIGNAL ;
    PORT
      LAYER M4 ;
        RECT  21.516 17.232 21.6 17.256 ;
    END
  END o[76]
  PIN o[77]
    DIRECTION OUTPUT ;
    USE SIGNAL ;
    PORT
      LAYER M4 ;
        RECT  21.516 17.328 21.6 17.352 ;
    END
  END o[77]
  PIN o[78]
    DIRECTION OUTPUT ;
    USE SIGNAL ;
    PORT
      LAYER M4 ;
        RECT  21.516 17.424 21.6 17.448 ;
    END
  END o[78]
  PIN o[79]
    DIRECTION OUTPUT ;
    USE SIGNAL ;
    PORT
      LAYER M4 ;
        RECT  21.516 17.52 21.6 17.544 ;
    END
  END o[79]
  PIN o[7]
    DIRECTION OUTPUT ;
    USE SIGNAL ;
    PORT
      LAYER M4 ;
        RECT  21.516 7.536 21.6 7.56 ;
    END
  END o[7]
  PIN o[80]
    DIRECTION OUTPUT ;
    USE SIGNAL ;
    PORT
      LAYER M4 ;
        RECT  21.516 17.616 21.6 17.64 ;
    END
  END o[80]
  PIN o[81]
    DIRECTION OUTPUT ;
    USE SIGNAL ;
    PORT
      LAYER M4 ;
        RECT  21.516 17.712 21.6 17.736 ;
    END
  END o[81]
  PIN o[82]
    DIRECTION OUTPUT ;
    USE SIGNAL ;
    PORT
      LAYER M4 ;
        RECT  21.516 17.808 21.6 17.832 ;
    END
  END o[82]
  PIN o[83]
    DIRECTION OUTPUT ;
    USE SIGNAL ;
    PORT
      LAYER M4 ;
        RECT  21.516 17.904 21.6 17.928 ;
    END
  END o[83]
  PIN o[84]
    DIRECTION OUTPUT ;
    USE SIGNAL ;
    PORT
      LAYER M4 ;
        RECT  21.516 18 21.6 18.024 ;
    END
  END o[84]
  PIN o[85]
    DIRECTION OUTPUT ;
    USE SIGNAL ;
    PORT
      LAYER M4 ;
        RECT  21.516 18.096 21.6 18.12 ;
    END
  END o[85]
  PIN o[86]
    DIRECTION OUTPUT ;
    USE SIGNAL ;
    PORT
      LAYER M4 ;
        RECT  21.516 18.192 21.6 18.216 ;
    END
  END o[86]
  PIN o[87]
    DIRECTION OUTPUT ;
    USE SIGNAL ;
    PORT
      LAYER M4 ;
        RECT  21.516 18.288 21.6 18.312 ;
    END
  END o[87]
  PIN o[88]
    DIRECTION OUTPUT ;
    USE SIGNAL ;
    PORT
      LAYER M4 ;
        RECT  21.516 18.384 21.6 18.408 ;
    END
  END o[88]
  PIN o[89]
    DIRECTION OUTPUT ;
    USE SIGNAL ;
    PORT
      LAYER M4 ;
        RECT  21.516 18.48 21.6 18.504 ;
    END
  END o[89]
  PIN o[8]
    DIRECTION OUTPUT ;
    USE SIGNAL ;
    PORT
      LAYER M4 ;
        RECT  21.516 7.632 21.6 7.656 ;
    END
  END o[8]
  PIN o[90]
    DIRECTION OUTPUT ;
    USE SIGNAL ;
    PORT
      LAYER M4 ;
        RECT  21.516 18.576 21.6 18.6 ;
    END
  END o[90]
  PIN o[91]
    DIRECTION OUTPUT ;
    USE SIGNAL ;
    PORT
      LAYER M4 ;
        RECT  21.516 18.672 21.6 18.696 ;
    END
  END o[91]
  PIN o[92]
    DIRECTION OUTPUT ;
    USE SIGNAL ;
    PORT
      LAYER M4 ;
        RECT  21.516 18.768 21.6 18.792 ;
    END
  END o[92]
  PIN o[93]
    DIRECTION OUTPUT ;
    USE SIGNAL ;
    PORT
      LAYER M4 ;
        RECT  21.516 18.864 21.6 18.888 ;
    END
  END o[93]
  PIN o[94]
    DIRECTION OUTPUT ;
    USE SIGNAL ;
    PORT
      LAYER M4 ;
        RECT  21.516 18.96 21.6 18.984 ;
    END
  END o[94]
  PIN o[95]
    DIRECTION OUTPUT ;
    USE SIGNAL ;
    PORT
      LAYER M4 ;
        RECT  21.516 19.056 21.6 19.08 ;
    END
  END o[95]
  PIN o[96]
    DIRECTION OUTPUT ;
    USE SIGNAL ;
    PORT
      LAYER M4 ;
        RECT  21.516 13.008 21.6 13.032 ;
    END
  END o[96]
  PIN o[97]
    DIRECTION OUTPUT ;
    USE SIGNAL ;
    PORT
      LAYER M4 ;
        RECT  21.516 13.104 21.6 13.128 ;
    END
  END o[97]
  PIN o[98]
    DIRECTION OUTPUT ;
    USE SIGNAL ;
    PORT
      LAYER M4 ;
        RECT  21.516 13.2 21.6 13.224 ;
    END
  END o[98]
  PIN o[99]
    DIRECTION OUTPUT ;
    USE SIGNAL ;
    PORT
      LAYER M4 ;
        RECT  21.516 13.296 21.6 13.32 ;
    END
  END o[99]
  PIN o[9]
    DIRECTION OUTPUT ;
    USE SIGNAL ;
    PORT
      LAYER M4 ;
        RECT  21.516 7.728 21.6 7.752 ;
    END
  END o[9]
  PIN rs
    DIRECTION INPUT ;
    USE SIGNAL ;
    PORT
      LAYER M5 ;
        RECT  5.616 0 5.64 0.084 ;
    END
  END rs
  PIN VDD
    DIRECTION INOUT ;
    USE POWER ;
    PORT
      LAYER M5 ;
        RECT  18.792 2.151 18.912 19.449 ;
        RECT  16.092 2.151 16.212 19.449 ;
        RECT  13.392 2.151 13.512 19.449 ;
        RECT  10.692 2.151 10.812 19.449 ;
        RECT  7.992 2.151 8.112 19.449 ;
        RECT  5.292 2.151 5.412 19.449 ;
        RECT  2.592 2.151 2.712 19.449 ;
    END
  END VDD
  PIN VSS
    DIRECTION INOUT ;
    USE GROUND ;
    PORT
      LAYER M5 ;
        RECT  18.6 2.137 18.72 19.463 ;
        RECT  15.9 2.137 16.02 19.463 ;
        RECT  13.2 2.137 13.32 19.463 ;
        RECT  10.5 2.137 10.62 19.463 ;
        RECT  7.8 2.137 7.92 19.463 ;
        RECT  5.1 2.137 5.22 19.463 ;
        RECT  2.4 2.137 2.52 19.463 ;
    END
  END VSS
  # OT_OBS_CLOSED layer=M5 d_um=1.536 added=10
  OBS
    LAYER RVTN ;
     RECT  2.16 2.16 19.44 2.295 ;
     RECT  2.16 2.565 19.44 2.835 ;
     RECT  2.16 3.105 19.44 3.375 ;
     RECT  2.16 3.645 19.44 3.915 ;
     RECT  2.16 4.185 19.44 4.455 ;
     RECT  2.16 4.725 19.44 4.995 ;
     RECT  2.16 5.265 19.44 5.535 ;
     RECT  2.16 5.805 19.44 6.075 ;
     RECT  2.16 6.345 19.44 6.615 ;
     RECT  2.16 6.885 19.44 7.155 ;
     RECT  2.16 7.425 19.44 7.695 ;
     RECT  2.16 7.965 19.44 8.235 ;
     RECT  2.16 8.505 19.44 8.775 ;
     RECT  2.16 9.045 19.44 9.315 ;
     RECT  2.16 9.585 19.44 9.855 ;
     RECT  2.16 10.125 19.44 10.395 ;
     RECT  2.16 10.665 19.44 10.935 ;
     RECT  2.16 11.205 19.44 11.475 ;
     RECT  2.16 11.745 19.44 12.015 ;
     RECT  2.16 12.285 19.44 12.555 ;
     RECT  2.16 12.825 19.44 13.095 ;
     RECT  2.16 13.365 19.44 13.635 ;
     RECT  2.16 13.905 19.44 14.175 ;
     RECT  2.16 14.445 19.44 14.715 ;
     RECT  2.16 14.985 19.44 15.255 ;
     RECT  2.16 15.525 19.44 15.795 ;
     RECT  2.16 16.065 19.44 16.335 ;
     RECT  2.16 16.605 19.44 16.875 ;
     RECT  2.16 17.145 19.44 17.415 ;
     RECT  2.16 17.685 19.44 17.955 ;
     RECT  2.16 18.225 19.44 18.495 ;
     RECT  2.16 18.765 19.44 19.035 ;
     RECT  2.16 19.305 19.44 19.44 ;
    LAYER RVTP ;
     RECT  2.16 2.295 19.44 2.565 ;
     RECT  2.16 2.835 19.44 3.105 ;
     RECT  2.16 3.375 19.44 3.645 ;
     RECT  2.16 3.915 19.44 4.185 ;
     RECT  2.16 4.455 19.44 4.725 ;
     RECT  2.16 4.995 19.44 5.265 ;
     RECT  2.16 5.535 19.44 5.805 ;
     RECT  2.16 6.075 19.44 6.345 ;
     RECT  2.16 6.615 19.44 6.885 ;
     RECT  2.16 7.155 19.44 7.425 ;
     RECT  2.16 7.695 19.44 7.965 ;
     RECT  2.16 8.235 19.44 8.505 ;
     RECT  2.16 8.775 19.44 9.045 ;
     RECT  2.16 9.315 19.44 9.585 ;
     RECT  2.16 9.855 19.44 10.125 ;
     RECT  2.16 10.395 19.44 10.665 ;
     RECT  2.16 10.935 19.44 11.205 ;
     RECT  2.16 11.475 19.44 11.745 ;
     RECT  2.16 12.015 19.44 12.285 ;
     RECT  2.16 12.555 19.44 12.825 ;
     RECT  2.16 13.095 19.44 13.365 ;
     RECT  2.16 13.635 19.44 13.905 ;
     RECT  2.16 14.175 19.44 14.445 ;
     RECT  2.16 14.715 19.44 14.985 ;
     RECT  2.16 15.255 19.44 15.525 ;
     RECT  2.16 15.795 19.44 16.065 ;
     RECT  2.16 16.335 19.44 16.605 ;
     RECT  2.16 16.875 19.44 17.145 ;
     RECT  2.16 17.415 19.44 17.685 ;
     RECT  2.16 17.955 19.44 18.225 ;
     RECT  2.16 18.495 19.44 18.765 ;
     RECT  2.16 19.035 19.44 19.305 ;
    LAYER M1 ;
     RECT  2.16 2.151 19.44 19.449 ;
    LAYER M2 ;
     RECT  0.103 8.514 0.139 9.54 ;
     RECT  0.103 3.312 0.175 4.518 ;
     RECT  0.103 10.836 0.203 10.854 ;
     RECT  0.103 16.956 0.211 16.974 ;
     RECT  0.175 3.312 0.283 4.716 ;
     RECT  0.283 3.312 0.463 5.058 ;
     RECT  0.463 3.114 0.535 5.058 ;
     RECT  1.147 15.192 1.363 15.21 ;
     RECT  0.535 11.79 1.399 11.808 ;
     RECT  0.211 16.812 1.435 16.974 ;
     RECT  1.435 16.812 1.471 17.1 ;
     RECT  1.327 13.374 1.723 13.392 ;
     RECT  1.363 14.454 1.723 15.21 ;
     RECT  0.103 2.268 2.16 2.286 ;
     RECT  0.535 3.114 2.16 5.598 ;
     RECT  0.535 6.588 2.16 6.606 ;
     RECT  0.103 7.398 2.16 7.416 ;
     RECT  0.139 8.514 2.16 9.882 ;
     RECT  1.399 11.79 2.16 12.24 ;
     RECT  1.723 13.374 2.16 15.552 ;
     RECT  1.471 16.542 2.16 17.1 ;
     RECT  2.16 2.151 4.315 19.449 ;
     RECT  4.315 2.106 4.747 19.449 ;
     RECT  4.747 2.034 6.871 19.449 ;
     RECT  6.871 1.962 13.055 19.449 ;
     RECT  13.055 2.034 13.883 19.449 ;
     RECT  13.883 2.106 13.991 19.449 ;
     RECT  13.991 2.151 19.44 19.449 ;
     RECT  19.44 4.536 19.571 19.296 ;
     RECT  19.44 2.808 19.679 3.744 ;
     RECT  19.679 3.384 19.751 3.744 ;
     RECT  19.571 4.536 19.787 6.714 ;
     RECT  19.787 4.536 19.859 6.138 ;
     RECT  19.859 5.274 19.895 6.138 ;
     RECT  19.895 5.274 19.931 5.364 ;
     RECT  19.571 7.596 19.967 19.296 ;
     RECT  19.895 6.12 20.003 6.138 ;
     RECT  19.967 7.596 20.507 18.018 ;
     RECT  19.967 18.774 20.507 19.296 ;
     RECT  20.507 7.704 20.543 16.866 ;
     RECT  20.507 18 20.543 18.018 ;
     RECT  20.543 7.704 20.579 8.802 ;
     RECT  20.579 8.784 20.615 8.802 ;
     RECT  20.543 9.936 20.615 13.194 ;
     RECT  20.543 15.156 21.343 16.794 ;
     RECT  21.343 15.156 21.407 17.478 ;
     RECT  21.407 17.46 21.415 17.478 ;
     RECT  20.507 18.972 21.415 19.296 ;
     RECT  20.615 11.016 21.479 12.546 ;
     RECT  21.407 15.606 21.479 16.434 ;
     RECT  21.415 17.46 21.479 18.18 ;
     RECT  20.579 7.704 21.487 7.722 ;
     RECT  21.487 7.632 21.515 7.722 ;
     RECT  20.615 9.936 21.515 9.954 ;
     RECT  21.479 11.016 21.515 12.384 ;
     RECT  21.479 16.416 21.515 16.434 ;
     RECT  21.479 18.162 21.515 18.18 ;
     RECT  21.415 18.972 21.515 19.494 ;
     RECT  19.931 5.346 21.551 5.364 ;
     RECT  21.451 6.858 21.551 6.876 ;
     RECT  19.751 3.726 21.587 3.744 ;
     RECT  21.515 7.632 21.587 7.65 ;
    LAYER M3 ;
     RECT  5.544 0.139 5.562 0.365 ;
     RECT  7.164 1.723 7.182 1.957 ;
     RECT  6.876 1.957 7.182 2.029 ;
     RECT  4.752 2.029 4.77 2.101 ;
     RECT  10.8 2.029 10.89 2.101 ;
     RECT  13.032 1.957 13.05 2.101 ;
     RECT  13.86 2.029 13.878 2.101 ;
     RECT  4.32 2.101 4.77 2.143 ;
     RECT  6.876 2.029 7.614 2.143 ;
     RECT  9.936 2.029 9.954 2.143 ;
     RECT  10.728 2.101 10.89 2.143 ;
     RECT  12.96 2.101 13.05 2.143 ;
     RECT  13.86 2.101 13.986 2.143 ;
     RECT  9.936 2.143 10.89 2.191 ;
     RECT  18.615 2.143 18.705 2.191 ;
     RECT  4.32 2.143 5.205 2.263 ;
     RECT  5.976 2.101 5.994 2.263 ;
     RECT  6.876 2.143 7.905 2.293 ;
     RECT  4.32 2.263 5.994 2.299 ;
     RECT  6.768 2.293 7.905 2.299 ;
     RECT  9.72 2.191 10.89 2.299 ;
     RECT  12.96 2.143 13.986 2.299 ;
     RECT  2.415 2.143 2.505 2.335 ;
     RECT  3.384 2.227 3.402 2.335 ;
     RECT  4.32 2.299 8.73 2.335 ;
     RECT  9.72 2.299 10.962 2.335 ;
     RECT  15.915 2.143 16.005 2.335 ;
     RECT  2.415 2.335 3.402 2.371 ;
     RECT  15.408 2.335 16.005 2.413 ;
     RECT  16.884 2.263 16.902 2.413 ;
     RECT  17.64 2.191 18.705 2.413 ;
     RECT  2.415 2.371 3.438 2.443 ;
     RECT  15.408 2.413 16.902 2.461 ;
     RECT  17.64 2.413 18.897 2.461 ;
     RECT  12.78 2.299 13.986 2.497 ;
     RECT  15.408 2.461 18.897 2.497 ;
     RECT  4.32 2.335 10.962 2.569 ;
     RECT  14.868 2.497 18.897 2.641 ;
     RECT  14.868 2.641 18.99 2.731 ;
     RECT  14.832 2.731 18.99 2.803 ;
     RECT  2.304 2.443 3.438 2.827 ;
     RECT  4.32 2.569 10.998 2.827 ;
     RECT  12.708 2.497 13.986 2.875 ;
     RECT  12.672 2.875 13.986 2.911 ;
     RECT  14.832 2.803 19.674 2.911 ;
     RECT  12.636 2.911 19.674 3.067 ;
     RECT  0.108 2.263 0.126 3.109 ;
     RECT  12.492 3.067 19.674 3.137 ;
     RECT  2.304 2.827 10.998 3.145 ;
     RECT  12.564 3.137 13.914 3.173 ;
     RECT  0.108 3.109 0.486 3.181 ;
     RECT  2.196 3.145 10.998 3.341 ;
     RECT  0.108 3.181 0.522 3.379 ;
     RECT  2.304 3.341 10.998 3.379 ;
     RECT  14.904 3.137 19.674 3.379 ;
     RECT  2.304 3.379 11.43 3.407 ;
     RECT  0.108 3.379 0.558 3.437 ;
     RECT  4.536 3.407 11.43 3.569 ;
     RECT  2.304 3.407 3.798 3.839 ;
     RECT  4.536 3.569 11.07 3.875 ;
     RECT  12.6 3.173 13.914 4.081 ;
     RECT  14.904 3.379 19.746 4.081 ;
     RECT  12.6 4.081 19.746 4.117 ;
     RECT  4.536 3.875 10.926 4.216 ;
     RECT  0.108 3.437 0.522 4.219 ;
     RECT  0.108 4.219 0.558 4.289 ;
     RECT  12.492 4.117 19.746 4.289 ;
     RECT  0.108 4.289 0.486 4.301 ;
     RECT  12.492 4.289 13.914 4.423 ;
     RECT  14.832 4.289 19.746 4.531 ;
     RECT  0.108 4.301 0.342 4.589 ;
     RECT  2.304 3.839 3.69 4.657 ;
     RECT  4.464 4.216 10.926 4.657 ;
     RECT  0.144 4.589 0.342 4.685 ;
     RECT  2.304 4.657 10.926 4.747 ;
     RECT  14.832 4.531 19.854 5.021 ;
     RECT  2.304 4.747 11.07 5.035 ;
     RECT  12.42 4.423 13.914 5.071 ;
     RECT  12.42 5.071 14.274 5.189 ;
     RECT  0.18 4.685 0.342 5.261 ;
     RECT  15.012 5.021 19.854 5.269 ;
     RECT  21.564 3.721 21.582 5.341 ;
     RECT  0.252 5.261 0.342 5.357 ;
     RECT  2.268 5.035 11.07 5.495 ;
     RECT  12.42 5.189 13.914 5.531 ;
     RECT  0.288 5.357 0.342 5.575 ;
     RECT  12.42 5.531 13.497 5.611 ;
     RECT  2.304 5.495 11.07 5.639 ;
     RECT  0.288 5.575 0.558 5.837 ;
     RECT  2.304 5.639 11.034 5.999 ;
     RECT  0.324 5.837 0.558 6.029 ;
     RECT  11.988 5.611 13.497 6.035 ;
     RECT  2.304 5.999 10.998 6.071 ;
     RECT  15.012 5.269 19.926 6.115 ;
     RECT  12.06 6.035 13.497 6.143 ;
     RECT  15.012 6.115 19.998 6.619 ;
     RECT  14.724 6.619 19.998 6.691 ;
     RECT  2.304 6.071 10.926 6.809 ;
     RECT  14.292 6.691 19.998 6.809 ;
     RECT  21.528 5.341 21.582 6.853 ;
     RECT  0.54 6.029 0.558 6.893 ;
     RECT  2.304 6.809 9.234 7.051 ;
     RECT  12.6 6.143 13.497 7.087 ;
     RECT  2.268 7.051 9.234 7.187 ;
     RECT  12.492 7.087 13.497 7.321 ;
     RECT  21.456 6.853 21.582 7.531 ;
     RECT  14.472 6.809 19.998 7.591 ;
     RECT  10.008 6.809 10.926 7.627 ;
     RECT  21.312 7.531 21.582 7.655 ;
     RECT  21.312 7.655 21.51 7.661 ;
     RECT  10.008 7.627 10.998 7.663 ;
     RECT  2.268 7.187 9.198 7.727 ;
     RECT  14.472 7.591 20.502 7.735 ;
     RECT  11.988 7.321 13.497 7.889 ;
     RECT  10.008 7.663 11.034 7.933 ;
     RECT  12.276 7.889 13.497 7.961 ;
     RECT  2.304 7.727 9.198 8.011 ;
     RECT  10.008 7.933 11.43 8.011 ;
     RECT  21.456 7.661 21.51 8.045 ;
     RECT  2.304 8.011 11.43 8.069 ;
     RECT  0.108 7.393 0.126 8.107 ;
     RECT  21.456 8.045 21.474 8.141 ;
     RECT  2.304 8.069 11.07 8.231 ;
     RECT  0.108 8.107 0.342 8.237 ;
     RECT  14.256 7.735 20.502 8.275 ;
     RECT  14.256 8.275 20.574 8.717 ;
     RECT  12.276 7.961 12.294 8.735 ;
     RECT  20.484 8.717 20.574 8.779 ;
     RECT  2.304 8.231 2.934 8.971 ;
     RECT  3.672 8.231 11.07 8.971 ;
     RECT  13.215 7.961 13.497 9.013 ;
     RECT  14.256 8.717 19.566 9.013 ;
     RECT  0.108 8.237 0.162 9.053 ;
     RECT  12.168 8.977 12.186 9.247 ;
     RECT  2.304 8.971 11.07 9.259 ;
     RECT  12.024 9.247 12.186 9.293 ;
     RECT  2.304 9.259 11.142 9.383 ;
     RECT  12.096 9.293 12.186 9.383 ;
     RECT  20.484 8.779 20.61 9.389 ;
     RECT  12.168 9.383 12.186 9.629 ;
     RECT  2.304 9.383 8.802 9.779 ;
     RECT  0.108 9.053 0.126 9.859 ;
     RECT  12.312 9.823 12.33 9.859 ;
     RECT  13.215 9.013 19.566 9.859 ;
     RECT  9.72 9.383 11.142 9.895 ;
     RECT  1.404 9.739 1.422 10.027 ;
     RECT  2.304 9.779 6.75 10.027 ;
     RECT  12.312 9.859 19.566 10.049 ;
     RECT  9.72 9.895 11.178 10.229 ;
     RECT  7.524 9.779 8.802 10.267 ;
     RECT  9.72 10.229 11.106 10.267 ;
     RECT  20.484 9.389 20.574 10.39 ;
     RECT  20.448 10.39 20.574 10.541 ;
     RECT  1.404 10.027 6.75 10.561 ;
     RECT  7.524 10.267 11.106 10.561 ;
     RECT  12.708 10.049 19.566 10.589 ;
     RECT  20.484 10.541 20.574 10.669 ;
     RECT  0.108 9.859 0.162 10.828 ;
     RECT  0.108 10.828 0.198 11.117 ;
     RECT  11.952 10.867 11.97 11.165 ;
     RECT  1.404 10.561 11.106 11.179 ;
     RECT  12.816 10.589 19.566 11.479 ;
     RECT  20.484 10.669 20.61 11.479 ;
     RECT  12.816 11.479 20.61 11.551 ;
     RECT  0.18 11.117 0.198 11.563 ;
     RECT  0.18 11.563 0.342 11.785 ;
     RECT  12.204 11.551 20.61 12.019 ;
     RECT  0.18 11.785 0.558 12.269 ;
     RECT  0.18 12.269 0.342 12.331 ;
     RECT  12.204 12.019 20.718 12.353 ;
     RECT  1.332 11.179 11.106 12.451 ;
     RECT  12.24 12.353 20.718 12.461 ;
     RECT  1.332 12.451 11.142 12.487 ;
     RECT  21.492 9.835 21.51 12.523 ;
     RECT  0.108 12.331 0.342 12.557 ;
     RECT  21.456 12.523 21.51 12.653 ;
     RECT  1.332 12.487 11.214 12.793 ;
     RECT  1.332 12.793 11.43 13.003 ;
     RECT  12.24 12.461 20.646 13.019 ;
     RECT  15.444 13.019 20.646 13.091 ;
     RECT  1.152 13.003 11.43 13.361 ;
     RECT  12.24 13.019 14.67 13.801 ;
     RECT  15.48 13.091 20.646 13.901 ;
     RECT  0.108 12.557 0.126 13.963 ;
     RECT  21.492 12.653 21.51 14.093 ;
     RECT  12.24 13.801 14.706 14.521 ;
     RECT  15.48 13.901 19.422 14.521 ;
     RECT  20.52 13.901 20.646 14.539 ;
     RECT  20.52 14.539 21.366 14.827 ;
     RECT  12.24 14.521 19.422 14.957 ;
     RECT  20.52 14.827 21.438 15.053 ;
     RECT  1.152 13.361 11.142 15.215 ;
     RECT  20.484 15.061 20.502 15.223 ;
     RECT  1.44 15.215 11.142 15.451 ;
     RECT  12.24 14.957 19.17 15.451 ;
     RECT  21.348 15.053 21.438 15.499 ;
     RECT  1.44 15.451 19.17 15.557 ;
     RECT  2.376 15.557 19.17 15.799 ;
     RECT  19.944 15.223 20.502 15.799 ;
     RECT  21.348 15.499 21.51 15.979 ;
     RECT  2.376 15.799 20.502 16.097 ;
     RECT  2.415 16.097 20.502 16.259 ;
     RECT  11.7 16.259 20.502 16.301 ;
     RECT  21.276 15.979 21.51 16.397 ;
     RECT  21.312 16.397 21.51 16.439 ;
     RECT  11.7 16.301 19.422 16.529 ;
     RECT  1.44 15.557 1.494 16.565 ;
     RECT  20.16 16.301 20.502 16.645 ;
     RECT  2.415 16.259 10.926 16.673 ;
     RECT  10.296 16.673 10.926 16.799 ;
     RECT  20.16 16.645 20.574 16.943 ;
     RECT  0.108 13.963 0.234 16.979 ;
     RECT  20.196 16.943 20.574 16.979 ;
     RECT  2.415 16.673 9.486 17.035 ;
     RECT  10.296 16.799 10.854 17.069 ;
     RECT  1.44 16.565 1.458 17.105 ;
     RECT  2.304 17.035 9.486 17.221 ;
     RECT  2.268 17.221 9.486 17.261 ;
     RECT  20.484 16.979 20.574 17.261 ;
     RECT  0.18 16.979 0.234 17.323 ;
     RECT  21.312 16.439 21.402 17.323 ;
     RECT  21.276 17.323 21.402 17.419 ;
     RECT  10.296 17.069 10.797 17.491 ;
     RECT  0.18 17.323 0.342 17.645 ;
     RECT  21.276 17.419 21.474 17.645 ;
     RECT  12.276 16.529 19.422 17.653 ;
     RECT  2.304 17.261 9.486 17.717 ;
     RECT  11.952 17.653 19.422 17.761 ;
     RECT  2.304 17.717 7.002 17.915 ;
     RECT  7.776 17.717 9.486 17.923 ;
     RECT  10.26 17.491 10.797 17.923 ;
     RECT  20.484 17.261 20.502 17.989 ;
     RECT  7.776 17.923 10.797 18.023 ;
     RECT  20.484 17.989 20.538 18.029 ;
     RECT  11.88 17.761 19.422 18.031 ;
     RECT  2.34 17.915 7.002 18.149 ;
     RECT  7.815 18.023 8.226 18.149 ;
     RECT  21.312 17.645 21.474 18.157 ;
     RECT  2.34 18.149 6.858 18.185 ;
     RECT  9.036 18.023 9.162 18.185 ;
     RECT  2.376 18.185 6.858 18.221 ;
     RECT  9.144 18.185 9.162 18.221 ;
     RECT  21.312 18.157 21.51 18.221 ;
     RECT  10.26 18.023 10.797 18.427 ;
     RECT  11.7 18.031 19.422 18.427 ;
     RECT  2.376 18.221 6.786 18.455 ;
     RECT  10.26 18.427 19.422 18.464 ;
     RECT  11.7 18.464 19.422 18.565 ;
     RECT  10.26 18.464 10.797 18.599 ;
     RECT  2.376 18.455 5.67 18.689 ;
     RECT  11.7 18.565 19.962 18.689 ;
     RECT  21.312 18.221 21.402 18.701 ;
     RECT  2.376 18.689 3.546 18.725 ;
     RECT  11.88 18.689 19.962 18.749 ;
     RECT  13.215 18.749 19.962 18.76 ;
     RECT  4.32 18.689 5.67 18.761 ;
     RECT  11.88 18.749 12.402 18.797 ;
     RECT  13.215 18.76 20.502 18.797 ;
     RECT  6.768 18.455 6.786 18.869 ;
     RECT  2.415 18.725 3.546 18.959 ;
     RECT  13.215 18.797 19.926 18.959 ;
     RECT  2.415 18.959 2.862 18.995 ;
     RECT  14.832 18.959 19.926 19.067 ;
     RECT  4.824 18.761 5.67 19.139 ;
     RECT  19.908 19.067 19.926 19.139 ;
     RECT  2.415 18.995 2.697 19.187 ;
     RECT  7.815 18.149 8.097 19.187 ;
     RECT  10.515 18.599 10.797 19.187 ;
     RECT  5.115 19.139 5.67 19.229 ;
     RECT  12.384 18.797 12.402 19.229 ;
     RECT  14.832 19.067 19.134 19.229 ;
     RECT  15.264 19.229 18.954 19.265 ;
     RECT  13.215 18.959 13.698 19.277 ;
     RECT  5.115 19.229 5.562 19.301 ;
     RECT  18 19.265 18.954 19.337 ;
     RECT  15.372 19.265 17.046 19.373 ;
     RECT  18 19.337 18.81 19.373 ;
     RECT  18.144 19.373 18.81 19.409 ;
     RECT  2.415 19.187 2.505 19.457 ;
     RECT  5.115 19.301 5.205 19.457 ;
     RECT  7.815 19.187 7.905 19.457 ;
     RECT  10.515 19.187 10.605 19.457 ;
     RECT  13.215 19.277 13.305 19.457 ;
     RECT  21.42 18.955 21.51 19.499 ;
     RECT  21.42 19.499 21.438 19.517 ;
     RECT  15.372 19.373 16.506 19.613 ;
     RECT  18.216 19.409 18.81 19.613 ;
     RECT  15.372 19.613 16.074 19.661 ;
     RECT  16.056 19.661 16.074 19.757 ;
     RECT  18.216 19.613 18.234 19.853 ;
    LAYER M4 ;
     RECT  0.06 2.448 2.365 14.664 ;
     RECT  2.365 2.448 2.408 14.808 ;
     RECT  0.06 17.04 2.408 17.736 ;
     RECT  2.408 2.148 2.512 19.452 ;
     RECT  2.512 2.418 2.704 19.182 ;
     RECT  2.704 7.632 2.765 9.048 ;
     RECT  2.704 10.32 2.765 14.664 ;
     RECT  2.704 2.544 2.801 6.6 ;
     RECT  2.765 7.728 2.801 9.048 ;
     RECT  2.704 16.56 2.801 17.736 ;
     RECT  2.801 2.544 2.837 6.408 ;
     RECT  2.801 7.92 2.837 9.048 ;
     RECT  2.837 2.544 2.873 3.048 ;
     RECT  2.801 17.616 2.873 17.736 ;
     RECT  2.837 4.224 3.089 6.408 ;
     RECT  2.837 8.112 3.089 9.048 ;
     RECT  3.089 5.664 3.197 6.408 ;
     RECT  2.765 10.32 3.197 14.52 ;
     RECT  2.873 17.616 3.197 17.64 ;
     RECT  3.197 10.8 3.341 14.52 ;
     RECT  2.873 2.544 3.413 2.856 ;
     RECT  3.089 8.112 3.413 9 ;
     RECT  3.413 8.112 3.805 8.808 ;
     RECT  3.341 12.624 3.925 14.52 ;
     RECT  2.801 16.56 3.925 16.584 ;
     RECT  3.925 12.624 3.971 16.584 ;
     RECT  3.971 12.624 4.097 15.672 ;
     RECT  3.805 7.392 4.165 8.808 ;
     RECT  4.165 7.104 4.489 8.808 ;
     RECT  3.341 10.8 4.525 11.16 ;
     RECT  3.413 2.832 4.561 2.856 ;
     RECT  3.089 4.224 4.633 4.248 ;
     RECT  4.561 2.784 4.705 2.856 ;
     RECT  4.633 3.888 4.705 4.248 ;
     RECT  3.197 5.664 4.741 6.12 ;
     RECT  4.705 2.496 4.777 4.248 ;
     RECT  4.741 5.52 4.777 6.12 ;
     RECT  4.525 10.8 4.777 11.208 ;
     RECT  4.777 2.496 4.813 6.12 ;
     RECT  4.489 7.104 4.813 9.72 ;
     RECT  4.777 10.8 4.849 11.256 ;
     RECT  4.813 2.496 5.108 9.72 ;
     RECT  4.849 10.8 5.108 11.784 ;
     RECT  4.097 12.864 5.108 15.672 ;
     RECT  4.885 17.616 5.108 17.64 ;
     RECT  5.108 2.148 5.212 19.452 ;
     RECT  5.212 2.148 5.404 19.182 ;
     RECT  5.404 2.148 5.461 15.48 ;
     RECT  5.461 0.24 5.489 0.264 ;
     RECT  5.489 0.144 5.516 0.264 ;
     RECT  5.404 17.616 5.555 18.216 ;
     RECT  5.516 0.144 5.573 0.36 ;
     RECT  5.573 0.24 5.603 0.36 ;
     RECT  5.603 0.24 5.651 0.264 ;
     RECT  5.461 1.728 5.789 15.48 ;
     RECT  5.789 1.728 6.275 14.856 ;
     RECT  6.275 1.728 7.193 14.424 ;
     RECT  7.193 2.148 7.397 14.424 ;
     RECT  7.397 2.148 7.808 15.336 ;
     RECT  7.405 17.088 7.808 17.112 ;
     RECT  5.555 18.192 7.808 18.216 ;
     RECT  7.808 2.148 7.912 19.452 ;
     RECT  7.912 2.304 8.104 19.182 ;
     RECT  8.104 2.304 8.165 15.336 ;
     RECT  8.104 17.088 8.569 17.928 ;
     RECT  8.165 2.544 8.849 15.336 ;
     RECT  8.849 2.544 8.921 15.288 ;
     RECT  8.921 2.544 8.993 15.24 ;
     RECT  8.993 2.544 9.389 14.712 ;
     RECT  8.569 17.904 9.425 17.928 ;
     RECT  9.389 2.544 10.508 10.68 ;
     RECT  9.389 11.76 10.508 14.712 ;
     RECT  10.508 2.148 10.612 19.452 ;
     RECT  10.612 2.418 10.804 19.182 ;
     RECT  10.804 2.544 10.901 11.784 ;
     RECT  10.901 8.688 10.973 11.784 ;
     RECT  10.804 14.736 10.973 14.76 ;
     RECT  10.901 2.544 11.009 7.656 ;
     RECT  10.973 8.784 11.045 11.784 ;
     RECT  10.804 18.432 13.093 18.456 ;
     RECT  11.009 2.544 13.208 7.368 ;
     RECT  11.045 8.784 13.208 10.344 ;
     RECT  11.045 11.76 13.208 11.784 ;
     RECT  10.804 13.008 13.208 13.032 ;
     RECT  11.833 15.456 13.208 15.48 ;
     RECT  12.841 16.512 13.208 16.536 ;
     RECT  13.093 18.432 13.208 18.744 ;
     RECT  13.208 2.148 13.312 19.452 ;
     RECT  13.312 2.418 13.504 19.272 ;
     RECT  13.504 2.544 13.709 7.368 ;
     RECT  13.504 8.784 13.709 10.344 ;
     RECT  13.709 8.784 14.321 9.048 ;
     RECT  13.504 11.76 14.321 11.784 ;
     RECT  14.321 8.784 14.501 8.808 ;
     RECT  13.709 2.736 14.861 7.368 ;
     RECT  14.861 2.784 14.933 7.128 ;
     RECT  13.504 18.624 15.073 19.272 ;
     RECT  13.504 15.456 15.289 15.48 ;
     RECT  15.073 17.664 15.361 19.272 ;
     RECT  15.397 11.424 15.649 11.448 ;
     RECT  15.289 12.48 15.865 12.504 ;
     RECT  14.933 2.784 15.908 7.08 ;
     RECT  13.709 10.32 15.908 10.344 ;
     RECT  15.649 11.424 15.908 11.496 ;
     RECT  15.865 12.48 15.908 12.552 ;
     RECT  15.289 14.64 15.908 15.48 ;
     RECT  15.361 17.664 15.908 19.656 ;
     RECT  15.908 2.148 16.012 19.656 ;
     RECT  16.012 2.418 16.045 19.656 ;
     RECT  16.045 2.418 16.204 19.752 ;
     RECT  16.204 2.784 17.093 5.016 ;
     RECT  17.093 2.784 17.165 2.856 ;
     RECT  16.204 10.32 17.201 19.752 ;
     RECT  17.201 10.368 17.309 19.752 ;
     RECT  17.093 4.176 17.453 5.016 ;
     RECT  17.453 4.992 17.561 5.016 ;
     RECT  17.485 7.44 18.205 7.464 ;
     RECT  17.309 11.424 18.205 19.752 ;
     RECT  17.165 2.784 18.608 2.808 ;
     RECT  18.205 7.44 18.608 7.656 ;
     RECT  17.309 10.368 18.608 10.44 ;
     RECT  18.205 11.424 18.608 19.848 ;
     RECT  18.608 2.148 18.712 19.848 ;
     RECT  18.712 2.418 18.904 19.848 ;
     RECT  18.904 6.864 19.933 11.88 ;
     RECT  18.904 13.008 19.933 19.848 ;
     RECT  19.933 6.864 21.564 19.848 ;
    LAYER M5 ;
     RECT  5.52 0.016 5.64 0.229 ;
     RECT  5.472 0.229 5.64 0.275 ;
     RECT  5.472 0.275 5.592 2.137 ;
     RECT  2.4 2.137 2.52 2.151 ;
     RECT  7.8 2.137 7.92 2.151 ;
     RECT  10.5 2.137 10.62 2.151 ;
     RECT  13.2 2.137 13.32 2.151 ;
     RECT  15.9 2.137 16.02 2.151 ;
     RECT  18.6 2.137 18.72 2.151 ;
     RECT  9.312 2.533 9.336 2.675 ;
     RECT  7.8 2.151 8.112 2.677 ;
     RECT  6.864 2.677 8.112 2.867 ;
     RECT  5.1 2.137 5.592 3.925 ;
     RECT  4.8 3.925 5.592 4.595 ;
     RECT  0.192 4.933 0.216 5.123 ;
     RECT  7.44 2.867 8.112 5.459 ;
     RECT  7.8 5.459 8.112 5.845 ;
     RECT  0.144 5.989 0.168 6.179 ;
     RECT  7.8 5.845 8.52 7.813 ;
     RECT  5.1 4.595 5.592 7.909 ;
     RECT  7.68 7.813 8.52 7.955 ;
     RECT  0.144 8.197 0.168 8.483 ;
     RECT  7.68 7.955 8.112 9.347 ;
     RECT  5.1 7.909 6.264 10.067 ;
     RECT  5.1 10.067 5.832 11.989 ;
     RECT  0.144 11.509 0.168 12.707 ;
     RECT  2.4 2.151 2.712 13.045 ;
     RECT  2.4 13.045 3.336 14.101 ;
     RECT  2.4 14.101 3.96 14.147 ;
     RECT  7.8 9.347 8.112 14.197 ;
     RECT  5.1 11.989 6.264 14.867 ;
     RECT  7.8 14.197 8.616 14.963 ;
     RECT  5.1 14.867 5.592 15.059 ;
     RECT  7.8 14.963 8.52 15.301 ;
     RECT  21.408 16.213 21.432 16.403 ;
     RECT  3.936 14.147 3.96 16.595 ;
     RECT  20.064 16.837 20.088 17.075 ;
     RECT  7.44 15.301 8.52 17.123 ;
     RECT  0.144 17.413 0.168 17.603 ;
     RECT  21.408 17.365 21.432 17.651 ;
     RECT  5.1 15.059 5.544 17.939 ;
     RECT  2.4 14.147 2.712 19.449 ;
     RECT  5.1 17.939 5.412 19.449 ;
     RECT  7.8 17.123 8.112 19.449 ;
     RECT  10.5 2.151 10.812 19.449 ;
     RECT  13.2 2.151 13.512 19.449 ;
     RECT  15.9 2.151 16.212 19.449 ;
     RECT  18.6 2.151 18.912 19.449 ;
     RECT  2.4 19.449 2.52 19.463 ;
     RECT  5.1 19.449 5.22 19.463 ;
     RECT  7.8 19.449 7.92 19.463 ;
     RECT  10.5 19.449 10.62 19.463 ;
     RECT  13.2 19.449 13.32 19.463 ;
     RECT  15.9 19.449 16.02 19.463 ;
     RECT  18.6 19.449 18.72 19.463 ;
     RECT  8.112 2.533 9.312 2.675 ;
     RECT  9.336 2.533 10.5 2.675 ;
     RECT  5.592 2.677 6.864 2.867 ;
     RECT  6.264 7.909 7.68 9.347 ;
     RECT  3.96 14.101 5.1 16.595 ;
     RECT  2.712 14.147 3.936 16.595 ;
     RECT  21.408 16.403 21.432 16.837 ;
     RECT  18.912 16.837 20.064 17.075 ;
     RECT  20.088 16.837 21.432 17.075 ;
     RECT  21.408 17.075 21.432 17.365 ;
  END
END hbfd_rly_136_WE
END LIBRARY
